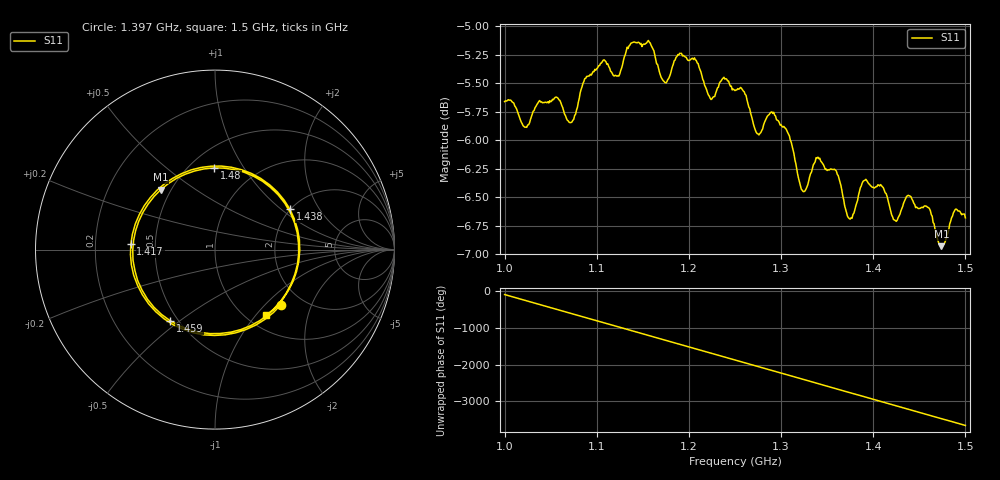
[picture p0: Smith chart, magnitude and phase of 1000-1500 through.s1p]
! NanoVNA-App by SYSJOINT et al v1.1.209 (+OD18)
! Date: 2025-09-17 10:18:51
! Start: 1GHz Stop: 1.5GHz Points: 501
! S-Parameter data: F S11
# Hz S RI R 50
!  Frequency  S11_Real  S11_Imag
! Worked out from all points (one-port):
!   501 points, 1 GHz to 1.5 GHz, reference 50 ohm
!   lowest |S11| = -6.9 dB at 1.474 GHz (marker M1), VSWR 2.64, Z = 22.1 + j18.5 ohm
!   |S11| at or under -10 dB: nowhere
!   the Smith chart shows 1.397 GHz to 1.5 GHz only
!   S11 on the Smith chart (normalised r, x): 1.397 GHz: 1.55, -1.24; 1.417 GHz: 0.36, +0.03; 1.438 GHz: 1.99, +1.15; 1.459 GHz: 0.45, -0.46; 1.48 GHz: 0.65, +0.75; 1.5 GHz: 1.21, -1.13
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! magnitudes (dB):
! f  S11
! 1 GHz  -5.7
! 1.022 GHz  -5.9
! 1.063 GHz  -5.7
! 1.073 GHz  -5.8
! 1.106 GHz  -5.3
! 1.125 GHz  -5.4
! 1.139 GHz  -5.1
! 1.157 GHz  -5.1
! 1.174 GHz  -5.5
! 1.188 GHz  -5.2
! 1.208 GHz  -5.3
! 1.223 GHz  -5.6
! 1.25 GHz  -5.6
! 1.274 GHz  -5.9
! 1.291 GHz  -5.8
! 1.313 GHz  -6.1
! 1.324 GHz  -6.5
! 1.34 GHz  -6.1
! 1.359 GHz  -6.3
! 1.375 GHz  -6.7
! 1.397 GHz  -6.4
! 1.417 GHz  -6.6
! 1.425 GHz  -6.7
! 1.438 GHz  -6.5
! 1.459 GHz  -6.6
! 1.474 GHz  -6.9
! 1.48 GHz  -6.8
! 1.5 GHz  -6.7
